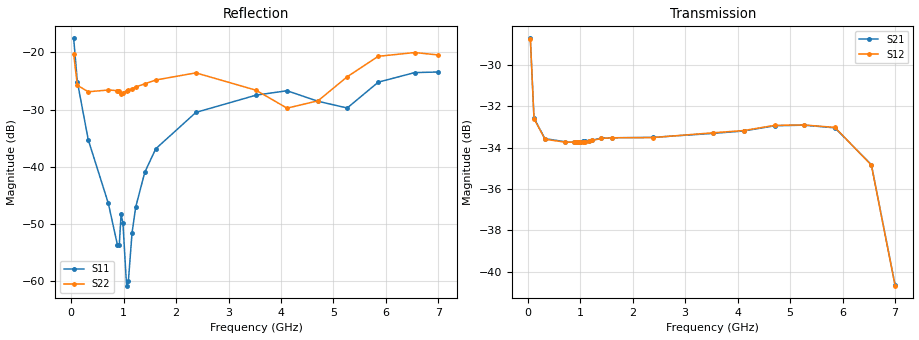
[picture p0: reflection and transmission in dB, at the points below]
! Integrated Device Technology
! Corporate Headquarters
! 6024 Silver Creek Valley Road
! San Jose, CA 95138  USA
! Phone:  1-408-284-8200
! Toll Free:  1-800-223-1366
! Webpage:  http://www.idt.com/
! Timing and RF Division
! 515 Groton Road, Suite 102
! Westford, MA 01886-6024
! Device:  F2258
! Description: Voltage Variable RF Attenuator
! Frequency:  50.0 -  6000.00 MHz
! Package:  3x3 mm Thin QFN Plastic Package: 16 pin
! Ports:  2 RF, 2 DC
!  Pin  1  = NC
!  Pin  2  = NC
!  Pin  3  = RF2  = Port 2
!  Pin  4  = GND
!  Pin  5  = Vdd
!  Pin  6  = NC
!  Pin  7  = VCTRL
!  Pin  8  = NC
!  Pin  9  = GND
!  Pin 10  = RF1  = Port 1
!  Pin 11  = NC
!  Pin 12  = NC
!  Pin 13  = NC
!  Pin 14  = NC
!  Pin 15  = NC
!  Pin 16  = NC
! Vcntrl:  1.820 Volts
! Vdd:  +3.300 Volts
! Current:  1.158 mA
! Data:  The device was measured on a the F2258 evaluation board which has
!  individual transmission lines to the RF pins.  Data was collected
!  using a calibrated network analyzer.  The evaluation board was
!  de-embedded using a TRL calibration technique.
!  The reference plane is the edge of the package pin.
! Misc:  SN 10
!  Action Tracker AT0285
! Date Measured:  2014-12-10
! Date:  2016-01-13  MJV
! Note:
!  Integrated Device Technology supplies this data as a sample of measured
!  data at the package pin for this product.  Your particular data for this
!  product may vary.
!  Data was taken at 25 degrees C.
!  Integrated Device Technology reserves the right to change this data at anytime.
!Freq_(GHz)  S11M_(dB)  S11P_(deg)  S21M_(dB)  S21P_(deg)  S12M_(dB)  S12P_(deg)  S22M_(dB)  S22P_(deg)
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# GHz S dB R 50
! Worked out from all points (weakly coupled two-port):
!   201 points, 50 MHz to 7 GHz, reference 50 ohm
!   highest |S21| = -28.73 dB at 50 MHz (marker M1); lowest = -40.6 dB at 7 GHz (marker M2)
!   lowest |S11| = -60.8 dB at 1.058 GHz (marker M3), VSWR 1.00, Z = 49.9 + j0.0446 ohm
!   |S11| at or under -10 dB: start of sweep to end of sweep
!   |S22| runs from -30.2 to -19.6 dB; largest |S21 - S12| = 9.2e-05
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0.05  -17.54 -110.7  -28.73 -61.6  -28.74 -61.6  -20.29 -94.6
0.1195  -25.12 -106.3  -32.58 -32.5  -32.60 -32.6  -25.76 -50.0
0.328  -35.31 -113.5  -33.57 -14.2  -33.60 -14.2  -26.89 -16.9
0.71025  -46.43 -132.8  -33.72 -9.7  -33.74 -9.7  -26.58 -5.4
0.884  -53.72 168.3  -33.73 -9.3  -33.74 -9.3  -26.69 -5.6
0.91875  -53.72 147.7  -33.74 -9.3  -33.75 -9.3  -26.76 -5.6
0.9535  -48.31 -159.2  -33.74 -9.3  -33.75 -9.3  -27.26 -3.0
0.98825  -49.84 -170.6  -33.72 -9.3  -33.73 -9.3  -27.13 -4.0
1.05775  -60.84 150.5  -33.70 -9.3  -33.72 -9.3  -26.73 -3.7
1.0925  -60.00 103.8  -33.69 -9.3  -33.71 -9.3  -26.64 -3.7
1.162  -51.61 61.2  -33.67 -9.5  -33.69 -9.4  -26.37 -3.7
1.2315  -47.08 41.0  -33.65 -9.7  -33.66 -9.6  -26.05 -3.9
1.40525  -40.97 31.4  -33.54 -10.6  -33.56 -10.6  -25.50 -3.4
1.61375  -36.87 31.3  -33.53 -11.9  -33.53 -11.9  -24.83 -4.8
2.37825  -30.51 47.3  -33.51 -16.4  -33.52 -16.3  -23.58 -4.3
3.525  -27.48 91.2  -33.32 -23.9  -33.29 -24.0  -26.62 1.7
4.11575  -26.71 104.8  -33.20 -28.4  -33.18 -28.4  -29.76 -1.3
4.7065  -28.56 95.4  -32.95 -33.8  -32.93 -33.9  -28.47 -17.3
5.2625  -29.73 53.7  -32.92 -39.9  -32.91 -40.0  -24.26 -28.9
5.85325  -25.21 29.5  -33.05 -49.9  -33.03 -49.8  -20.68 -32.8
6.54825  -23.53 44.8  -34.83 -68.1  -34.85 -68.1  -20.02 -60.4
7  -23.43 84.3  -40.63 -65.3  -40.67 -65.0  -20.45 -123.7
